VERSION 5.7 ;
BUSBITCHARS "[]" ;
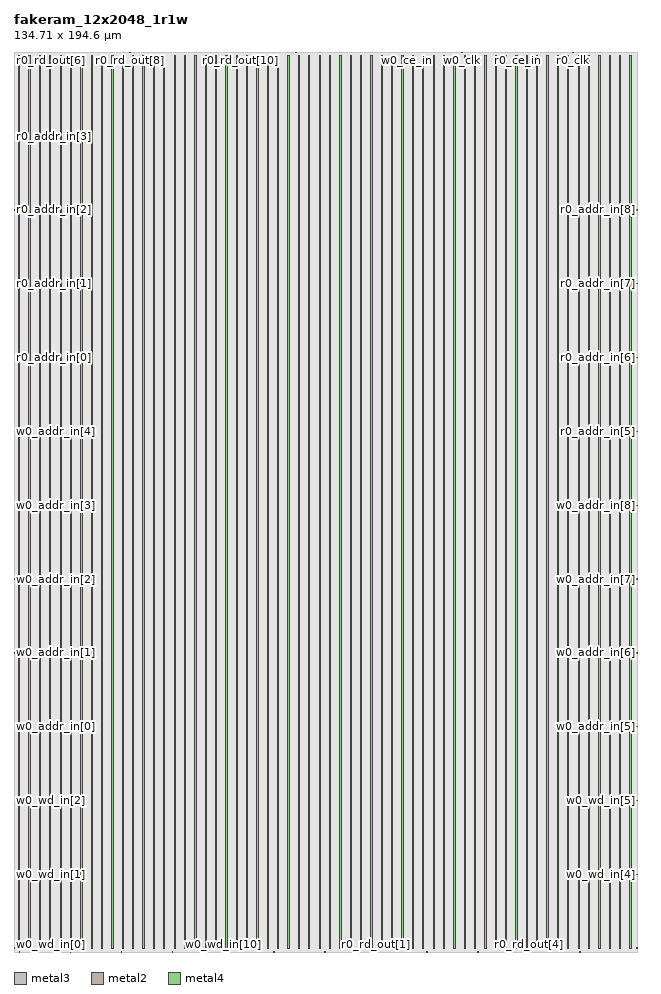
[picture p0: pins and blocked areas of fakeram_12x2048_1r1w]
MACRO fakeram_12x2048_1r1w
  FOREIGN fakeram_12x2048_1r1w 0 0 ;
  SYMMETRY X Y R90 ;
  SIZE 134.710 BY 194.600 ;
  CLASS BLOCK ;
  PIN w0_wd_in[0]
    DIRECTION INPUT ;
    USE SIGNAL ;
    SHAPE ABUTMENT ;
    PORT
      LAYER metal3 ;
      RECT 0.000 0.805 0.210 0.875 ;
    END
  END w0_wd_in[0]
  PIN w0_wd_in[1]
    DIRECTION INPUT ;
    USE SIGNAL ;
    SHAPE ABUTMENT ;
    PORT
      LAYER metal3 ;
      RECT 0.000 16.765 0.210 16.835 ;
    END
  END w0_wd_in[1]
  PIN w0_wd_in[2]
    DIRECTION INPUT ;
    USE SIGNAL ;
    SHAPE ABUTMENT ;
    PORT
      LAYER metal3 ;
      RECT 0.000 32.725 0.210 32.795 ;
    END
  END w0_wd_in[2]
  PIN w0_wd_in[3]
    DIRECTION INPUT ;
    USE SIGNAL ;
    SHAPE ABUTMENT ;
    PORT
      LAYER metal3 ;
      RECT 134.500 0.805 134.710 0.875 ;
    END
  END w0_wd_in[3]
  PIN w0_wd_in[4]
    DIRECTION INPUT ;
    USE SIGNAL ;
    SHAPE ABUTMENT ;
    PORT
      LAYER metal3 ;
      RECT 134.500 16.765 134.710 16.835 ;
    END
  END w0_wd_in[4]
  PIN w0_wd_in[5]
    DIRECTION INPUT ;
    USE SIGNAL ;
    SHAPE ABUTMENT ;
    PORT
      LAYER metal3 ;
      RECT 134.500 32.725 134.710 32.795 ;
    END
  END w0_wd_in[5]
  PIN w0_wd_in[6]
    DIRECTION INPUT ;
    USE SIGNAL ;
    SHAPE ABUTMENT ;
    PORT
      LAYER metal2 ;
      RECT 1.105 0.000 1.175 0.210 ;
    END
  END w0_wd_in[6]
  PIN w0_wd_in[7]
    DIRECTION INPUT ;
    USE SIGNAL ;
    SHAPE ABUTMENT ;
    PORT
      LAYER metal2 ;
      RECT 12.125 0.000 12.195 0.210 ;
    END
  END w0_wd_in[7]
  PIN w0_wd_in[8]
    DIRECTION INPUT ;
    USE SIGNAL ;
    SHAPE ABUTMENT ;
    PORT
      LAYER metal2 ;
      RECT 23.145 0.000 23.215 0.210 ;
    END
  END w0_wd_in[8]
  PIN w0_wd_in[9]
    DIRECTION INPUT ;
    USE SIGNAL ;
    SHAPE ABUTMENT ;
    PORT
      LAYER metal2 ;
      RECT 34.165 0.000 34.235 0.210 ;
    END
  END w0_wd_in[9]
  PIN w0_wd_in[10]
    DIRECTION INPUT ;
    USE SIGNAL ;
    SHAPE ABUTMENT ;
    PORT
      LAYER metal2 ;
      RECT 45.185 0.000 45.255 0.210 ;
    END
  END w0_wd_in[10]
  PIN w0_wd_in[11]
    DIRECTION INPUT ;
    USE SIGNAL ;
    SHAPE ABUTMENT ;
    PORT
      LAYER metal2 ;
      RECT 56.205 0.000 56.275 0.210 ;
    END
  END w0_wd_in[11]
  PIN r0_rd_out[0]
    DIRECTION OUTPUT ;
    USE SIGNAL ;
    SHAPE ABUTMENT ;
    PORT
      LAYER metal2 ;
      RECT 67.225 0.000 67.295 0.210 ;
    END
  END r0_rd_out[0]
  PIN r0_rd_out[1]
    DIRECTION OUTPUT ;
    USE SIGNAL ;
    SHAPE ABUTMENT ;
    PORT
      LAYER metal2 ;
      RECT 78.245 0.000 78.315 0.210 ;
    END
  END r0_rd_out[1]
  PIN r0_rd_out[2]
    DIRECTION OUTPUT ;
    USE SIGNAL ;
    SHAPE ABUTMENT ;
    PORT
      LAYER metal2 ;
      RECT 89.265 0.000 89.335 0.210 ;
    END
  END r0_rd_out[2]
  PIN r0_rd_out[3]
    DIRECTION OUTPUT ;
    USE SIGNAL ;
    SHAPE ABUTMENT ;
    PORT
      LAYER metal2 ;
      RECT 100.285 0.000 100.355 0.210 ;
    END
  END r0_rd_out[3]
  PIN r0_rd_out[4]
    DIRECTION OUTPUT ;
    USE SIGNAL ;
    SHAPE ABUTMENT ;
    PORT
      LAYER metal2 ;
      RECT 111.305 0.000 111.375 0.210 ;
    END
  END r0_rd_out[4]
  PIN r0_rd_out[5]
    DIRECTION OUTPUT ;
    USE SIGNAL ;
    SHAPE ABUTMENT ;
    PORT
      LAYER metal2 ;
      RECT 122.325 0.000 122.395 0.210 ;
    END
  END r0_rd_out[5]
  PIN r0_rd_out[6]
    DIRECTION OUTPUT ;
    USE SIGNAL ;
    SHAPE ABUTMENT ;
    PORT
      LAYER metal2 ;
      RECT 1.105 194.390 1.175 194.600 ;
    END
  END r0_rd_out[6]
  PIN r0_rd_out[7]
    DIRECTION OUTPUT ;
    USE SIGNAL ;
    SHAPE ABUTMENT ;
    PORT
      LAYER metal2 ;
      RECT 13.075 194.390 13.145 194.600 ;
    END
  END r0_rd_out[7]
  PIN r0_rd_out[8]
    DIRECTION OUTPUT ;
    USE SIGNAL ;
    SHAPE ABUTMENT ;
    PORT
      LAYER metal2 ;
      RECT 25.045 194.390 25.115 194.600 ;
    END
  END r0_rd_out[8]
  PIN r0_rd_out[9]
    DIRECTION OUTPUT ;
    USE SIGNAL ;
    SHAPE ABUTMENT ;
    PORT
      LAYER metal2 ;
      RECT 37.015 194.390 37.085 194.600 ;
    END
  END r0_rd_out[9]
  PIN r0_rd_out[10]
    DIRECTION OUTPUT ;
    USE SIGNAL ;
    SHAPE ABUTMENT ;
    PORT
      LAYER metal2 ;
      RECT 48.985 194.390 49.055 194.600 ;
    END
  END r0_rd_out[10]
  PIN r0_rd_out[11]
    DIRECTION OUTPUT ;
    USE SIGNAL ;
    SHAPE ABUTMENT ;
    PORT
      LAYER metal2 ;
      RECT 60.955 194.390 61.025 194.600 ;
    END
  END r0_rd_out[11]
  PIN w0_addr_in[0]
    DIRECTION INPUT ;
    USE SIGNAL ;
    SHAPE ABUTMENT ;
    PORT
      LAYER metal3 ;
      RECT 0.000 48.685 0.210 48.755 ;
    END
  END w0_addr_in[0]
  PIN w0_addr_in[1]
    DIRECTION INPUT ;
    USE SIGNAL ;
    SHAPE ABUTMENT ;
    PORT
      LAYER metal3 ;
      RECT 0.000 64.645 0.210 64.715 ;
    END
  END w0_addr_in[1]
  PIN w0_addr_in[2]
    DIRECTION INPUT ;
    USE SIGNAL ;
    SHAPE ABUTMENT ;
    PORT
      LAYER metal3 ;
      RECT 0.000 80.605 0.210 80.675 ;
    END
  END w0_addr_in[2]
  PIN w0_addr_in[3]
    DIRECTION INPUT ;
    USE SIGNAL ;
    SHAPE ABUTMENT ;
    PORT
      LAYER metal3 ;
      RECT 0.000 96.565 0.210 96.635 ;
    END
  END w0_addr_in[3]
  PIN w0_addr_in[4]
    DIRECTION INPUT ;
    USE SIGNAL ;
    SHAPE ABUTMENT ;
    PORT
      LAYER metal3 ;
      RECT 0.000 112.525 0.210 112.595 ;
    END
  END w0_addr_in[4]
  PIN w0_addr_in[5]
    DIRECTION INPUT ;
    USE SIGNAL ;
    SHAPE ABUTMENT ;
    PORT
      LAYER metal3 ;
      RECT 134.500 48.685 134.710 48.755 ;
    END
  END w0_addr_in[5]
  PIN w0_addr_in[6]
    DIRECTION INPUT ;
    USE SIGNAL ;
    SHAPE ABUTMENT ;
    PORT
      LAYER metal3 ;
      RECT 134.500 64.645 134.710 64.715 ;
    END
  END w0_addr_in[6]
  PIN w0_addr_in[7]
    DIRECTION INPUT ;
    USE SIGNAL ;
    SHAPE ABUTMENT ;
    PORT
      LAYER metal3 ;
      RECT 134.500 80.605 134.710 80.675 ;
    END
  END w0_addr_in[7]
  PIN w0_addr_in[8]
    DIRECTION INPUT ;
    USE SIGNAL ;
    SHAPE ABUTMENT ;
    PORT
      LAYER metal3 ;
      RECT 134.500 96.565 134.710 96.635 ;
    END
  END w0_addr_in[8]
  PIN r0_addr_in[0]
    DIRECTION INPUT ;
    USE SIGNAL ;
    SHAPE ABUTMENT ;
    PORT
      LAYER metal3 ;
      RECT 0.000 128.485 0.210 128.555 ;
    END
  END r0_addr_in[0]
  PIN r0_addr_in[1]
    DIRECTION INPUT ;
    USE SIGNAL ;
    SHAPE ABUTMENT ;
    PORT
      LAYER metal3 ;
      RECT 0.000 144.445 0.210 144.515 ;
    END
  END r0_addr_in[1]
  PIN r0_addr_in[2]
    DIRECTION INPUT ;
    USE SIGNAL ;
    SHAPE ABUTMENT ;
    PORT
      LAYER metal3 ;
      RECT 0.000 160.405 0.210 160.475 ;
    END
  END r0_addr_in[2]
  PIN r0_addr_in[3]
    DIRECTION INPUT ;
    USE SIGNAL ;
    SHAPE ABUTMENT ;
    PORT
      LAYER metal3 ;
      RECT 0.000 176.365 0.210 176.435 ;
    END
  END r0_addr_in[3]
  PIN r0_addr_in[4]
    DIRECTION INPUT ;
    USE SIGNAL ;
    SHAPE ABUTMENT ;
    PORT
      LAYER metal3 ;
      RECT 0.000 192.325 0.210 192.395 ;
    END
  END r0_addr_in[4]
  PIN r0_addr_in[5]
    DIRECTION INPUT ;
    USE SIGNAL ;
    SHAPE ABUTMENT ;
    PORT
      LAYER metal3 ;
      RECT 134.500 112.525 134.710 112.595 ;
    END
  END r0_addr_in[5]
  PIN r0_addr_in[6]
    DIRECTION INPUT ;
    USE SIGNAL ;
    SHAPE ABUTMENT ;
    PORT
      LAYER metal3 ;
      RECT 134.500 128.485 134.710 128.555 ;
    END
  END r0_addr_in[6]
  PIN r0_addr_in[7]
    DIRECTION INPUT ;
    USE SIGNAL ;
    SHAPE ABUTMENT ;
    PORT
      LAYER metal3 ;
      RECT 134.500 144.445 134.710 144.515 ;
    END
  END r0_addr_in[7]
  PIN r0_addr_in[8]
    DIRECTION INPUT ;
    USE SIGNAL ;
    SHAPE ABUTMENT ;
    PORT
      LAYER metal3 ;
      RECT 134.500 160.405 134.710 160.475 ;
    END
  END r0_addr_in[8]
  PIN w0_we_in
    DIRECTION INPUT ;
    USE SIGNAL ;
    SHAPE ABUTMENT ;
    PORT
      LAYER metal2 ;
      RECT 72.925 194.390 72.995 194.600 ;
    END
  END w0_we_in
  PIN w0_ce_in
    DIRECTION INPUT ;
    USE SIGNAL ;
    SHAPE ABUTMENT ;
    PORT
      LAYER metal2 ;
      RECT 84.895 194.390 84.965 194.600 ;
    END
  END w0_ce_in
  PIN w0_clk
    DIRECTION INPUT ;
    USE SIGNAL ;
    SHAPE ABUTMENT ;
    PORT
      LAYER metal2 ;
      RECT 96.865 194.390 96.935 194.600 ;
    END
  END w0_clk
  PIN r0_ce_in
    DIRECTION INPUT ;
    USE SIGNAL ;
    SHAPE ABUTMENT ;
    PORT
      LAYER metal2 ;
      RECT 108.835 194.390 108.905 194.600 ;
    END
  END r0_ce_in
  PIN r0_clk
    DIRECTION INPUT ;
    USE SIGNAL ;
    SHAPE ABUTMENT ;
    PORT
      LAYER metal2 ;
      RECT 120.805 194.390 120.875 194.600 ;
    END
  END r0_clk
  PIN VSS
    DIRECTION INOUT ;
    USE GROUND ;
    PORT
      LAYER metal4 ;
      RECT 1.000 0.840 1.280 193.760 ;
      RECT 3.240 0.840 3.520 193.760 ;
      RECT 5.480 0.840 5.760 193.760 ;
      RECT 7.720 0.840 8.000 193.760 ;
      RECT 9.960 0.840 10.240 193.760 ;
      RECT 12.200 0.840 12.480 193.760 ;
      RECT 14.440 0.840 14.720 193.760 ;
      RECT 16.680 0.840 16.960 193.760 ;
      RECT 18.920 0.840 19.200 193.760 ;
      RECT 21.160 0.840 21.440 193.760 ;
      RECT 23.400 0.840 23.680 193.760 ;
      RECT 25.640 0.840 25.920 193.760 ;
      RECT 27.880 0.840 28.160 193.760 ;
      RECT 30.120 0.840 30.400 193.760 ;
      RECT 32.360 0.840 32.640 193.760 ;
      RECT 34.600 0.840 34.880 193.760 ;
      RECT 36.840 0.840 37.120 193.760 ;
      RECT 39.080 0.840 39.360 193.760 ;
      RECT 41.320 0.840 41.600 193.760 ;
      RECT 43.560 0.840 43.840 193.760 ;
      RECT 45.800 0.840 46.080 193.760 ;
      RECT 48.040 0.840 48.320 193.760 ;
      RECT 50.280 0.840 50.560 193.760 ;
      RECT 52.520 0.840 52.800 193.760 ;
      RECT 54.760 0.840 55.040 193.760 ;
      RECT 57.000 0.840 57.280 193.760 ;
      RECT 59.240 0.840 59.520 193.760 ;
      RECT 61.480 0.840 61.760 193.760 ;
      RECT 63.720 0.840 64.000 193.760 ;
      RECT 65.960 0.840 66.240 193.760 ;
      RECT 68.200 0.840 68.480 193.760 ;
      RECT 70.440 0.840 70.720 193.760 ;
      RECT 72.680 0.840 72.960 193.760 ;
      RECT 74.920 0.840 75.200 193.760 ;
      RECT 77.160 0.840 77.440 193.760 ;
      RECT 79.400 0.840 79.680 193.760 ;
      RECT 81.640 0.840 81.920 193.760 ;
      RECT 83.880 0.840 84.160 193.760 ;
      RECT 86.120 0.840 86.400 193.760 ;
      RECT 88.360 0.840 88.640 193.760 ;
      RECT 90.600 0.840 90.880 193.760 ;
      RECT 92.840 0.840 93.120 193.760 ;
      RECT 95.080 0.840 95.360 193.760 ;
      RECT 97.320 0.840 97.600 193.760 ;
      RECT 99.560 0.840 99.840 193.760 ;
      RECT 101.800 0.840 102.080 193.760 ;
      RECT 104.040 0.840 104.320 193.760 ;
      RECT 106.280 0.840 106.560 193.760 ;
      RECT 108.520 0.840 108.800 193.760 ;
      RECT 110.760 0.840 111.040 193.760 ;
      RECT 113.000 0.840 113.280 193.760 ;
      RECT 115.240 0.840 115.520 193.760 ;
      RECT 117.480 0.840 117.760 193.760 ;
      RECT 119.720 0.840 120.000 193.760 ;
      RECT 121.960 0.840 122.240 193.760 ;
      RECT 124.200 0.840 124.480 193.760 ;
      RECT 126.440 0.840 126.720 193.760 ;
      RECT 128.680 0.840 128.960 193.760 ;
      RECT 130.920 0.840 131.200 193.760 ;
      RECT 133.160 0.840 133.440 193.760 ;
    END
  END VSS
  PIN VDD
    DIRECTION INOUT ;
    USE POWER ;
    PORT
      LAYER metal4 ;
      RECT 1.000 0.840 1.280 193.760 ;
      RECT 3.240 0.840 3.520 193.760 ;
      RECT 5.480 0.840 5.760 193.760 ;
      RECT 7.720 0.840 8.000 193.760 ;
      RECT 9.960 0.840 10.240 193.760 ;
      RECT 12.200 0.840 12.480 193.760 ;
      RECT 14.440 0.840 14.720 193.760 ;
      RECT 16.680 0.840 16.960 193.760 ;
      RECT 18.920 0.840 19.200 193.760 ;
      RECT 21.160 0.840 21.440 193.760 ;
      RECT 23.400 0.840 23.680 193.760 ;
      RECT 25.640 0.840 25.920 193.760 ;
      RECT 27.880 0.840 28.160 193.760 ;
      RECT 30.120 0.840 30.400 193.760 ;
      RECT 32.360 0.840 32.640 193.760 ;
      RECT 34.600 0.840 34.880 193.760 ;
      RECT 36.840 0.840 37.120 193.760 ;
      RECT 39.080 0.840 39.360 193.760 ;
      RECT 41.320 0.840 41.600 193.760 ;
      RECT 43.560 0.840 43.840 193.760 ;
      RECT 45.800 0.840 46.080 193.760 ;
      RECT 48.040 0.840 48.320 193.760 ;
      RECT 50.280 0.840 50.560 193.760 ;
      RECT 52.520 0.840 52.800 193.760 ;
      RECT 54.760 0.840 55.040 193.760 ;
      RECT 57.000 0.840 57.280 193.760 ;
      RECT 59.240 0.840 59.520 193.760 ;
      RECT 61.480 0.840 61.760 193.760 ;
      RECT 63.720 0.840 64.000 193.760 ;
      RECT 65.960 0.840 66.240 193.760 ;
      RECT 68.200 0.840 68.480 193.760 ;
      RECT 70.440 0.840 70.720 193.760 ;
      RECT 72.680 0.840 72.960 193.760 ;
      RECT 74.920 0.840 75.200 193.760 ;
      RECT 77.160 0.840 77.440 193.760 ;
      RECT 79.400 0.840 79.680 193.760 ;
      RECT 81.640 0.840 81.920 193.760 ;
      RECT 83.880 0.840 84.160 193.760 ;
      RECT 86.120 0.840 86.400 193.760 ;
      RECT 88.360 0.840 88.640 193.760 ;
      RECT 90.600 0.840 90.880 193.760 ;
      RECT 92.840 0.840 93.120 193.760 ;
      RECT 95.080 0.840 95.360 193.760 ;
      RECT 97.320 0.840 97.600 193.760 ;
      RECT 99.560 0.840 99.840 193.760 ;
      RECT 101.800 0.840 102.080 193.760 ;
      RECT 104.040 0.840 104.320 193.760 ;
      RECT 106.280 0.840 106.560 193.760 ;
      RECT 108.520 0.840 108.800 193.760 ;
      RECT 110.760 0.840 111.040 193.760 ;
      RECT 113.000 0.840 113.280 193.760 ;
      RECT 115.240 0.840 115.520 193.760 ;
      RECT 117.480 0.840 117.760 193.760 ;
      RECT 119.720 0.840 120.000 193.760 ;
      RECT 121.960 0.840 122.240 193.760 ;
      RECT 124.200 0.840 124.480 193.760 ;
      RECT 126.440 0.840 126.720 193.760 ;
      RECT 128.680 0.840 128.960 193.760 ;
      RECT 130.920 0.840 131.200 193.760 ;
      RECT 133.160 0.840 133.440 193.760 ;
    END
  END VDD
  OBS
    LAYER metal1 ;
    RECT 0 0 134.710 194.600 ;
    LAYER metal2 ;
    RECT 0 0 134.710 194.600 ;
    LAYER metal3 ;
    RECT 0 0 134.710 194.600 ;
    LAYER metal4 ;
    RECT 0 0 134.710 194.600 ;
    LAYER OVERLAP ;
    RECT 0 0 134.710 194.600 ;
  END
END fakeram_12x2048_1r1w

END LIBRARY
